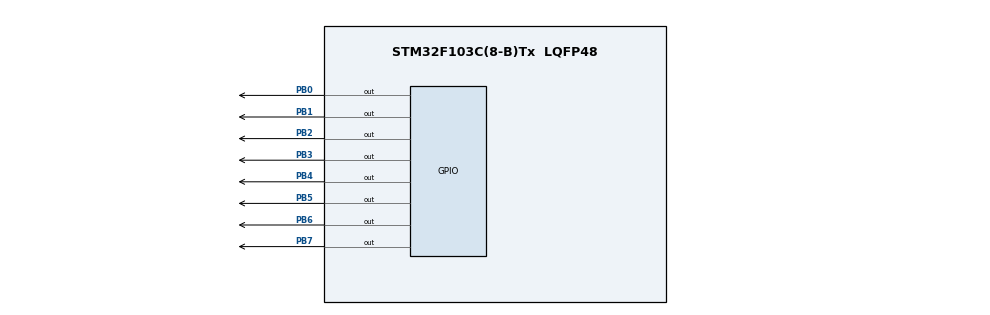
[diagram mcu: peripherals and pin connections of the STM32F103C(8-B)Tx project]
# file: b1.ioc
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Mcu.Family=STM32F1
Mcu.Name=STM32F103C(8-B)Tx
Mcu.Package=LQFP48
NVIC.PriorityGroup=NVIC_PRIORITYGROUP_4
PA13.Mode=Serial_Wire
PA13.Signal=SYS_JTMS-SWDIO
PA14.Mode=Serial_Wire
PA14.Signal=SYS_JTCK-SWCLK
PB0.Signal=GPIO_Output
PB1.Signal=GPIO_Output
PB2.Signal=GPIO_Output
PB3.Signal=GPIO_Output
PB4.Signal=GPIO_Output
PB5.Signal=GPIO_Output
PB6.Signal=GPIO_Output
PB7.Signal=GPIO_Output
ProjectManager.HeapSize=0x200
ProjectManager.StackSize=0x400
ProjectManager.TargetToolchain=MDK-ARM V5.32
RCC.APB1Freq_Value=8000000
RCC.APB2Freq_Value=8000000
board=custom

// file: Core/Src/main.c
/* USER CODE BEGIN Header */
/**
  ******************************************************************************
  * @file           : main.c
  * @brief          : Main program body
  ******************************************************************************
  * @attention
  *
  * Copyright (c) 2022 STMicroelectronics.
  * All rights reserved.
  *
  * This software is licensed under terms that can be found in the LICENSE file
  * in the root directory of this software component.
  * If no LICENSE file comes with this software, it is provided AS-IS.
  *
  ******************************************************************************
  */
/* USER CODE END Header */
#include "main.h"

/* USER CODE BEGIN PV */
	int cnt = 0;
	int cnt1 = 8;
/* USER CODE END PV */

void SystemClock_Config(void);
static void MX_GPIO_Init(void);

int main(void)
{

  /* MCU Configuration--------------------------------------------------------*/

  /* Reset of all peripherals, Initializes the Flash interface and the Systick. */
  HAL_Init();

  /* Configure the system clock */
  SystemClock_Config();

  /* Initialize all configured peripherals */
  MX_GPIO_Init();
  /* USER CODE BEGIN 2 */
	//GPIOB->ODR = 0x00FF;
	//HAL_GPIO_WritePin(GPIOB, GPIO_PIN_0|GPIO_PIN_1|GPIO_PIN_2|GPIO_PIN_3
  //                        |GPIO_PIN_4|GPIO_PIN_5|GPIO_PIN_6|GPIO_PIN_7, 0);
	//HAL_GPIO_WritePin(GPIOB,0x00FF);
  /* USER CODE END 2 */

  /* Infinite loop */
  while (1)
  {

    /* USER CODE BEGIN 3 */ //cnt = 0
		if(cnt<=8) // sang dan
		{
			GPIOB->ODR=0xff>>cnt;
			HAL_Delay(200); //delay
			cnt++;  // tang bien count
		}
		else //
		{
			if(cnt1>=0) //tat dan cnt1=8
			{
				GPIOB->ODR=0xff<<cnt1;
				HAL_Delay(200);
				cnt1--; //
			}
			else //cnt1<0
			{
				cnt = 0;
				cnt1 = 8;
			}
		}
		}
  /* USER CODE END 3 */
}

void SystemClock_Config(void)
{
  RCC_OscInitTypeDef RCC_OscInitStruct = {0};
  RCC_ClkInitTypeDef RCC_ClkInitStruct = {0};

  /** Initializes the RCC Oscillators according to the specified parameters
  * in the RCC_OscInitTypeDef structure.
  */
  RCC_OscInitStruct.OscillatorType = RCC_OSCILLATORTYPE_HSI;
  RCC_OscInitStruct.HSIState = RCC_HSI_ON;
  RCC_OscInitStruct.HSICalibrationValue = RCC_HSICALIBRATION_DEFAULT;
  RCC_OscInitStruct.PLL.PLLState = RCC_PLL_NONE;
  if (HAL_RCC_OscConfig(&RCC_OscInitStruct) != HAL_OK)
  {
    Error_Handler();
  }

  /** Initializes the CPU, AHB and APB buses clocks
  */
  RCC_ClkInitStruct.ClockType = RCC_CLOCKTYPE_HCLK|RCC_CLOCKTYPE_SYSCLK
                              |RCC_CLOCKTYPE_PCLK1|RCC_CLOCKTYPE_PCLK2;
  RCC_ClkInitStruct.SYSCLKSource = RCC_SYSCLKSOURCE_HSI;
  RCC_ClkInitStruct.AHBCLKDivider = RCC_SYSCLK_DIV1;
  RCC_ClkInitStruct.APB1CLKDivider = RCC_HCLK_DIV1;
  RCC_ClkInitStruct.APB2CLKDivider = RCC_HCLK_DIV1;

  if (HAL_RCC_ClockConfig(&RCC_ClkInitStruct, FLASH_LATENCY_0) != HAL_OK)
  {
    Error_Handler();
  }
}

static void MX_GPIO_Init(void)
{
  GPIO_InitTypeDef GPIO_InitStruct = {0};

  /* GPIO Ports Clock Enable */
  __HAL_RCC_GPIOA_CLK_ENABLE();
  __HAL_RCC_GPIOB_CLK_ENABLE();

  /*Configure GPIO pin Output Level */
  HAL_GPIO_WritePin(GPIOA, GPIO_PIN_0|GPIO_PIN_1|GPIO_PIN_2|GPIO_PIN_3
                          |GPIO_PIN_4|GPIO_PIN_5|GPIO_PIN_6|GPIO_PIN_7, GPIO_PIN_RESET);

  /*Configure GPIO pin Output Level */
  HAL_GPIO_WritePin(GPIOB, GPIO_PIN_0|GPIO_PIN_1|GPIO_PIN_2|GPIO_PIN_3
                          |GPIO_PIN_4|GPIO_PIN_5|GPIO_PIN_6|GPIO_PIN_7
                          |GPIO_PIN_8, GPIO_PIN_RESET);

  /*Configure GPIO pins : PA0 PA1 PA2 PA3
                           PA4 PA5 PA6 PA7 */
  GPIO_InitStruct.Pin = GPIO_PIN_0|GPIO_PIN_1|GPIO_PIN_2|GPIO_PIN_3
                          |GPIO_PIN_4|GPIO_PIN_5|GPIO_PIN_6|GPIO_PIN_7;
  GPIO_InitStruct.Mode = GPIO_MODE_OUTPUT_PP;
  GPIO_InitStruct.Pull = GPIO_NOPULL;
  GPIO_InitStruct.Speed = GPIO_SPEED_FREQ_LOW;
  HAL_GPIO_Init(GPIOA, &GPIO_InitStruct);

  /*Configure GPIO pins : PB0 PB1 PB2 PB3
                           PB4 PB5 PB6 PB7
                           PB8 */
  GPIO_InitStruct.Pin = GPIO_PIN_0|GPIO_PIN_1|GPIO_PIN_2|GPIO_PIN_3
                          |GPIO_PIN_4|GPIO_PIN_5|GPIO_PIN_6|GPIO_PIN_7
                          |GPIO_PIN_8;
  GPIO_InitStruct.Mode = GPIO_MODE_OUTPUT_PP;
  GPIO_InitStruct.Pull = GPIO_NOPULL;
  GPIO_InitStruct.Speed = GPIO_SPEED_FREQ_LOW;
  HAL_GPIO_Init(GPIOB, &GPIO_InitStruct);

}

void Error_Handler(void)
{
  __disable_irq();
  while (1)
  {
  }
}
